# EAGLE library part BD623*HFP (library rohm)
H-bridge driver for brush motors Source: http://www.rohm.com/products/databook/motor/pdf/bd623x_series-e.pdf

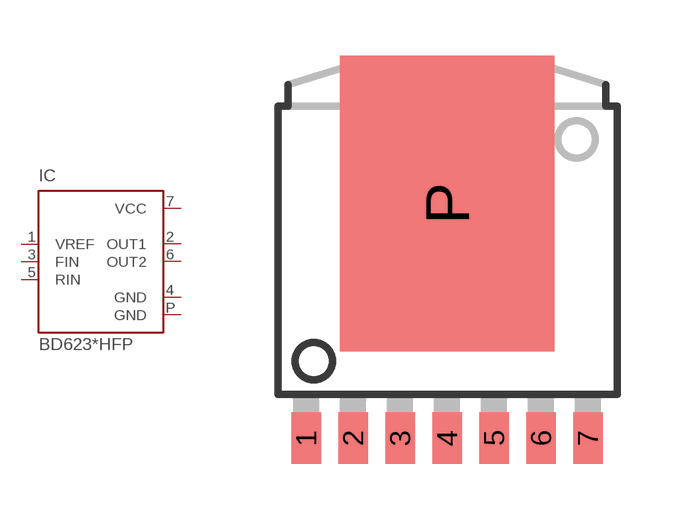
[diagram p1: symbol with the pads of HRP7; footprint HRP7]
Designator prefix IC

## BD6230HFP (OC_FARNELL: unknown; OC_NEWARK: unknown), BD6231HFP (MPN: BD6231HFP-TR; OC_FARNELL: 1712946; OC_NEWARK: 24R5626), BD6232HFP (MPN: BD6232HFP-TR; OC_FARNELL: 1712947; OC_NEWARK: 24R5627)  [HRP7]
1  VREF  pas
2  OUT1  out
3  FIN  in
4  GND  pwr
5  RIN  in
6  OUT2  out
7  VCC  pwr
P  GND  pwr

## Footprint HRP7 (pad centres in mm)
HRP7 Source: http://www.rohm.com/products/databook/motor/pdf/bd623x_series-e.pdf
smd 0.8 x 1.4: 1 -3.81,-5.08; 2 -2.54,-5.08; 3 -1.27,-5.08; 4 0,-5.08; 5 1.27,-5.08; 6 2.54,-5.08; 7 3.81,-5.08
smd 5.8 x 8: P 0,1.27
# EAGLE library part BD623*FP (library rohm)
H-bridge driver for brush motors Source: http://www.rohm.com/products/databook/motor/pdf/bd623x_series-e.pdf

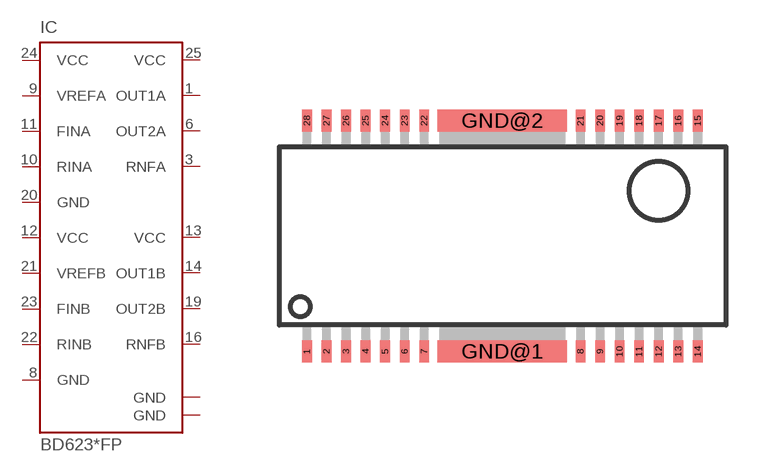
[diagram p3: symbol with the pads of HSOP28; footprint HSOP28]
Designator prefix IC

## BD623FP (OC_FARNELL: unknown; OC_NEWARK: unknown)  [HSOP28]
1  OUT1A  out
3  RNFA  pas
6  OUT2A  out
8  GND  pwr
9  VREFA  pas
10  RINA  in
11  FINA  in
12  VCC  pwr
13  VCC  pwr
14  OUT1B  out
16  RNFB  pas
19  OUT2B  out
20  GND  pwr
21  VREFB  pas
22  RINB  in
23  FINB  in
24  VCC  pwr
25  VCC  pwr
GND@1  GND  pwr
GND@2  GND  pwr

## Footprint HSOP28 (pad centres in mm)
HSOP-M28 Source: http://www.rohm.com/products/databook/motor/pdf/bd623x_series-e.pdf
smd 0.4 x 0.9: 1 -8,-4.725; 2 -7.2,-4.725; 3 -6.4,-4.725; 4 -5.6,-4.725; 5 -4.8,-4.725; 6 -4,-4.725; 7 -3.2,-4.725; 8 3.2,-4.725; 9 4,-4.725; 10 4.8,-4.725; 11 5.6,-4.725; 12 6.4,-4.725; 13 7.2,-4.725; 14 8,-4.725; 15 8,4.725; 16 7.2,4.725; 17 6.4,4.725; 18 5.6,4.725; 19 4.8,4.725; 20 4,4.725; 21 3.2,4.725; 22 -3.2,4.725; 23 -4,4.725; 24 -4.8,4.725; 25 -5.6,4.725; 26 -6.4,4.725; 27 -7.2,4.725; 28 -8,4.725
smd 5.3 x 0.9: GND@1 0,-4.725; GND@2 0,4.725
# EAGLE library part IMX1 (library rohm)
General purpose transistors (dual transistors) Two 2SC2412K chips in a EMT or UMT or SMT package. Source: http://www.rohm.com/products/databook/tr/pdf/umx1n.pdf

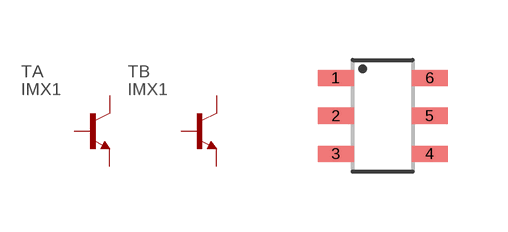
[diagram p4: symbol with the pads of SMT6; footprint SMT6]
Designator prefix T; gates A=NPN B=NPN

## IMX1 (MPN: IMX1T110; OC_FARNELL: 1680348; OC_NEWARK: 74M2434)  [SMT6]
1  A:C  pas
2  B:B  pas
3  B:E  pas
4  B:C  pas
5  A:B  pas
6  A:E  pas

## Footprint SMT6 (pad centres in mm)
SMT6 Package EIAJ : SC-74 Source: http://www.rohm.com/products/databook/tr/pdf/umx1n.pdf
smd 0.9 x 0.4: 1 -1.175,0.95; 2 -1.175,0; 3 -1.175,-0.95; 4 1.175,-0.95; 5 1.175,0; 6 1.175,0.95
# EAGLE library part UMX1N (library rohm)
General purpose transistors (dual transistors) Two 2SC2412K chips in a EMT or UMT or SMT package. Source: http://www.rohm.com/products/databook/tr/pdf/umx1n.pdf

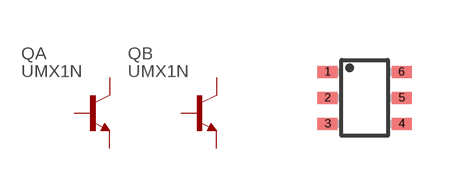
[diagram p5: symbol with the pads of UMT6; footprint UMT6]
Designator prefix Q; gates A=NPN B=NPN

## UMX1N (MPN: UMX1NTN; OC_FARNELL: 1680410; OC_NEWARK: 40P3417)  [UMT6]
1  A:E  pas
2  A:B  pas
3  B:C  pas
4  B:E  pas
5  B:B  pas
6  A:C  pas

## Footprint UMT6 (pad centres in mm)
UMT6 Package EIAJ: SC-88 Source: http://www.rohm.com/products/databook/tr/pdf/umx1n.pdf
smd 0.5 x 0.3: 1 -0.925,0.65; 2 -0.925,0; 3 -0.925,-0.65; 4 0.925,-0.65; 5 0.925,0; 6 0.925,0.65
